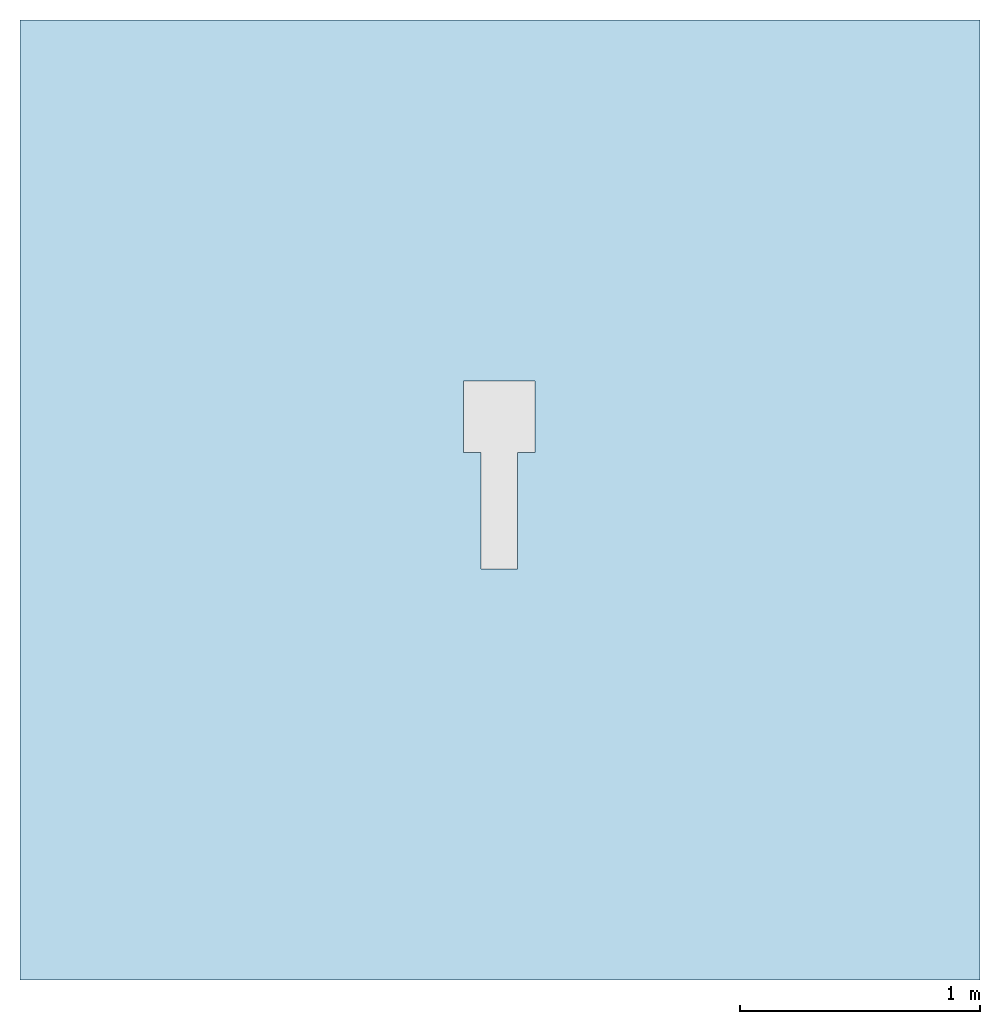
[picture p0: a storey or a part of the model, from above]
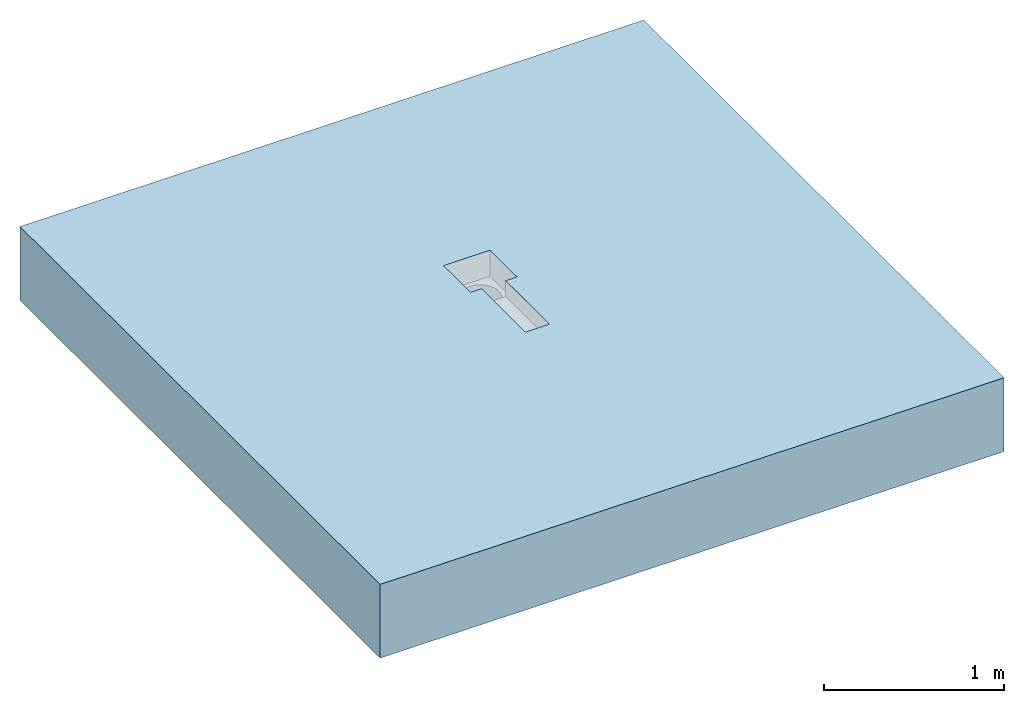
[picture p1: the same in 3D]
Properties of the parts of a building model (IFC2X3)

# File
Description: ViewDefinition [CoordinationView]
File name: 105376 - One Way Gully Top - 784 mm LG - Invert Depth 95mm.ifc
Time: 2014-03-19T12:21:46
Written by: Autodesk Revit 2013
Made in: 20120221_2030(x64)

# IfcProject, Project Number
LongName: Project Name; Phase: Project Status

# IfcSite, Default
RefLatitude: 42, 21, 30, 344238; RefLongitude: -71, -3, -35, -194702; RefElevation: 0 mm

# IfcBuilding
Pset_BuildingCommon - NumberOfStoreys: 1
Other - Client Name: Owner; Project Address: ## Street City, State Zip; Project Name: Project Name; Project Status: Project Status; Project Issue Date: Issue Date; Project Number: Project Number

# IfcBuildingStorey, Level 1
LongName: Level 1; Elevation: 0 mm
Graphics - Line Weight: 1; Symbol: M_Level Head - Circle: M_Level Head - Circle; Symbol at End 2 Default: yes; Color: 0; Line Pattern: Center; Symbol at End 1 Default: no
Constraints - Elevation Base: 0; Elevation: 0 mm
Dimensions - Computation Height: 0 mm
Identity Data - Structural: no; Name: Level 1; Building Story: yes

# IfcFlowTerminal: 105376 - One Way Gully Top - 784 mm LG - Invert Depth 95mm, ACO BD Modular 125 One and Two Way Gully Units:105376 - One Way Gully Top - 784 mm LG - Invert Depth 95mm:105376 - One Way Gully Top - 784 mm LG - Invert Depth 95mm:204969
In: Level 1
Material: Rubber, Nitrile, Stainless Steel AISI 304, Polystyrene, High Impact
Construction - Grating One Way: yes; Grating Two Way: no; Detail 125mm: no; Detail 65mm: no; Detail 95mm: yes; 49061 & 49062_Vinyl Seal: no; 402072 - Grating - Heal Safe Locked - Stainless Steel 304 - 500mm long: no; 105505 - Perforated Locked - Stainless Steel 304 - 500mm long: no; 408085_Telescopic_Horizontal Outlet Ø_110mm: no; 408067_Telescopic_Vertical Outlet Ø_160mm: no; 408223_Horizontal Outlet Gully Silt Basket: no; 105846 - Slip Resistant Intercept - Stainless Steel 304 - 500mm long: no; 408071_Telescopic_Vertical Outlet Ø_160mm: no; 105844 - Slip Resistant Quadrato Locked - Stainless Steel 304 - 500mm long: no; 408220_Outlet Foul Air Trap: yes; 408045 - Plain Ladder - Stainless Steel 304 - 268 x 268mm: no; 408041 - Slip Resistant Arla - Stainless Steel 304 - 268 x 268mm: no; 408039 - Slot Cover - Stainless Steel 304 - 268 x 268mm: no; 408038 - Ladder - Stainless Steel 304 - 268 x 268mm: no; 105537 - Intercept Locked - Stainless Steel 304 - 500mm long: no; 105848 - Slip Resistant Intercept Locked - Stainless Steel 304 - 500mm long: no; Min & Max Table for Vertical Gully Outlet: no; Min & Max Table for Horizontal Gully Outlet: no; 408065_Telescopic_Vertical Outlet Ø_110mm: no; 105842 - Slip Resistant Quadrato - Stainless Steel 304 - 500mm long: no; 10735 - Composite - White Composite - 500mm long: no; 15704 - Composite - Black Composite - 500mm long: no; 21910 - Grating - Slip Resistant Mesh - Stainless Steel 304 - 500mm long: no; 21790 - Plastic - White Plastic - 500mm long: no; 408069_Telescopic_Vertical Outlet Ø_160mm: no; 408037 - Slip Resistant Ladder - Stainless Steel 304 - 268 x 268mm: no; 408087_Telescopic_Horizontal Outlet Ø_110mm: no; 21740 - Ladder - Stainless Steel 304 - 500mm long: no; 26270_PVC Infill: yes; 408034 - Plain Mesh - Stainless Steel 304 - 268 x 268mm: no; 408089_Telescopic_Horizontal Outlet Ø_110mm: no; 408042 - Slip Resistant Multi Slot - Stainless Steel 304 - 268 x 268mm: no; 408040 - Heal Safe - Stainless Steel 304 - 268 x 268mm: no; 408035 - Slip Resistant Mesh - Stainless Steel 304 - 268 x 268mm: no; 408063_Telescopic_Vertical Outlet Ø_110mm: no; 408061_Telescopic_Vertical Outlet Ø_110mm: yes; 408036 - Quadrato - Stainless Steel 304 - 268 x 268mm: no; End Plate Invert 2: no; 96819 - Grating - Heal Safe - Stainless Steel 304 - 500mm long: no; 105519 - Slotted Locked - Stainless Steel 304 - 500mm long: no; 105521 - Slotted Locked - Stainless Steel 304 - 500mm long: no; 105528 - Quadrato Locked - Stainless Steel 304 - 500mm long: no; End Plate Invert 1: no; 408222_Verical Outlet Gully Silt Basket: yes; 105539 - Intercept - Stainless Steel 304 - 500mm long: no; 21710 - Grating - Slip Resistant Mesh - Stainless Steel 304 - 500mm long: no; 21920 - Grating - Plain Mesh - Stainless Steel 304 - 500mm long: no; 105530 - Quadrato - Stainless Steel 304 - 500mm long: no; 21720 - Grating - Plain Mesh - Stainless Steel 304 - 500mm long: no
Other - Rigid PVC Extrusion (49061): 0 mm; Neoprene Gasket: 1; 408089: 400 mm; 408063: 400 mm; PVC Infill Two Way: no; 408071: 400 mm; 408061: 0 mm; 408065: 400 mm; Silt Basket: yes; 408069: 400 mm; 408085: 400 mm; PVC Infill (26270): 1983 mm; 408067: 400 mm; 408087: 400 mm; Flexible PVC Seal (49062): 0 mm; One Way Detail 125mm: no; Two Way Detail 65mm: no; One Way Detail 65mm: no; One Way Channel: yes; Two Way Detail 125mm: no; Two Way Detail 95mm: no; One Way Detail 95mm: yes; Two Way Channel: no
Identity Data - Mark: 2; Watermarked By: www.acobd.com; Telephone: +44 (0)1462 816666; Manufacturer: ACO Building Drainage; E-mail Sales: abdcommercial@aco.co.uk; Website: www.acobd.com; Address: ACO Business Centre, Caxton Road, Bedford, MK41 0LF; E-mail Technical: abdtechnical@aco.co.uk; Fax: +44 (0)1462 851490; Watermark2: This file is water marked and users are prohibited to reproduce, adapt, distribute this information.; Watermark1: This file is the property of ACO Technologies PLC.; Watermarked With: BIM Manager Premium Suite.
Mechanical - System Classification: Sanitary
Dimensions - Silt Basket Height: 50 mm; Vertical Gully Void Height Start: -18.5 mm; Horizontal Gully Outlet Radius: 0 mm; Horizontal Gully Void Height Start: -1 mm; Vertical Gully Void Height End: -290.5 mm; Gully Floor Void Radius: 120 mm; Vertical Gully Outlet Radius: 55 mm; Horizontal Gully Void Height End: 1 mm; Gully Top Floor Void End: 176.25 mm; Depth: 74 mm; Channel Floor Void Height: 107.8 mm; Channel Floor Void End: 486 mm; Grating Height: 21 mm; Gully Height from Floor: 139 mm; PVC 1 or 2 way: 147.5 mm; Channel to Gully top cutter End: 121 mm; Total Height: 107.8 mm; Two Way PVC In Filll Start: -1.5 mm
Constraints - Level: Level: Level 1
Phasing - Phase Created: New Construction
General - Installation guidelines: X:\Electronic Literature\ABD Electronic Literature\Standard Stainless Steel and Galvanised Steel Channels\ACO Modular 125\ACO Modular 125.pdf; Product Code: 105376; Product Range: ACO Modular 125; Weight (Kg): 5.2; Product Description: ACO Modular 125 One Way Gully Top; NBS Specification: NBS Section Q10 Kerbs/edgings/channels/paving accessories, Clause 180 Drainage Channel Systems; Channel Material: Stainless Steel Grade 304; Channel Recyclable: Fully recyclable; Product Type: Stainless Steel Channel Drainage System; Price: POA - contact ACO; Seal Recyclable: Fully recyclable; Product Standard: BS EN 1433:2002, CE marked; Channel Colour: Mid Grey; Channel Recycled Material Content: 60-70%; Seal Colour: Black; Dimensions (LxWxH): 784 x 153 x 95; Load Class: A15 - C250; Seal Recycled Material Content: 0%; Maintenance guidelines: X:\Electronic Literature\ABD Electronic Literature\Standard Stainless Steel and Galvanised Steel Channels\ACO Modular 125\ACO Modular 125.pdf; Seal Material: Neoprene
Model Properties - Grating Product Code 402072: Load Class B125 - Heal Safe Locked - Stainless Steel 304 - 500mm long - 2.0kg; Grating Product Code 408035: Load Class L15 - Slip Resistant Mesh - Stainless Steel 304 - 268 x 268 mm - 2.1kg; Product Code 408223: Horizontal Outlet Gully - Silt Basket - 0.7 litre capacity - Stainless Steel 304 - 0.6kg; Grating Product Code 408037: Load Class M125 - Slip Resistant Ladder - Stainless Steel 304 - 268 x 268 mm - 4.3kg; Grating Product Code 105519: Load Class A15 - Slotted Locked - Stainless Steel 304 - 500mm long - 1.0kg; Product Code 408225: Friction Ring Installation Set - Nitrile - 0.09kg; Grating Product Code 408038: Load Class M125 - Plain Ladder - Stainless Steel 304 - 268 x 268 mm - 4.3kg; Grating Product Code 408039: Load Class M125 - Slot Cover - Stainless Steel 304 - 268 x 268 mm - 6.0kg; Gully Product Code 408063: Telescopic - 110mm Ø Vertical Outlet - Stainless Steel 304 - Adhesive Bonding Flange - Flow Rate 5.0 to 6.3 l/s - 4.4kg; Gully Product Code 408067: Telescopic - 160mm Ø Vertical Outlet - Stainless Steel 304 - Location Flange - Flow Rate 5.0 to 6.3 l/s - 3.2kg; Grating Product Code 96819: Load Class B125 - Heal Safe - Stainless Steel 304 - 500mm long - 2.0kg; Grating Product Code 15704: Load Class C250 - Composite - Black Composite - 500mm long - 1.2kg; Gully Product Code 408069: Telescopic - 160mm Ø Vertical Outlet - Stainless Steel 304 - Adhesive Bonding Flange - Flow Rate 5.0 to 6.3 l/s - 4.4kg; Gully Product Code 408061: Telescopic - 110mm Ø Vertical Outlet - Stainless Steel 304 - Location Flange - Flow Rate 5.0 to 6.3 l/s - 3.2kg; Grating Product Code 408041: Load Class L15 - Slip Resistant Arla - Stainless Steel 304 - 268 x 268 mm - 1.8kg; Grating Product Code 105848: Load Class A15 - Slip Resistant Intercept Locked - Stainless Steel 304 - 500mm long - 1.8kg; Grating Product Code 21920: Load Class C250 - Plain Mesh - Stainless Steel 304 - 500mm long - 2.2kg; Grating Product Code 21740: Load Class C250 - Ladder - Stainless Steel 304 - 500mm long - 2.0kg; Grating Product Code 408034: Load Class L15 - Plain Mesh - Stainless Steel 304 - 268 x 268 mm - 2.1kg; Grating Product Code 408040: Load Class L15 - Heal Safe - Stainless Steel 304 - 268 x 268 mm - 2.4kg; Gully Product Code 408065: Telescopic - 110mm Ø Vertical Outlet - Stainless Steel 304 - Mechanical Clamping Flange - Flow Rate 5.0 to 6.3 l/s - 5.5kg; Grating Product Code 408042: Load Class L15 - Slip Resistant Multi Slot - Stainless Steel 304 - 268 x 268 mm - 2.0kg; Grating Product Code 408045: Load Class C250 - Plain Ladder - Stainless Steel 304 - 268 x 268 mm - 6.2kg; Grating Product Code 105846: Load Class A15 - Slip Resistant Intercept - Stainless Steel 304 - 500mm long - 1.8kg; Product Code 408222: Vertical Outlet Gully - Silt Basket - 1.4 litre capacity - Stainless Steel 304 - 0.7kg; Grating Product Code 105844: Load Class A15 - Slip Resistant Quadrato Locked - Stainless Steel 304 - 500mm long - 1.6kg; Gully Product Code 408087: Telescopic - 110mm Ø Horizontal Outlet - Stainless Steel 304 - Adhesive Bonding Flange - Flow Rate 4.4 to 5.5 l/s - 4.2kg; Grating Product Code 21790: Load Class A15 - Plastic - White Plastic - 500mm long - 0.6kg; Grating Product Code 21910: Load Class C250 - Slip Resistant Mesh - Stainless Steel 304 - 500mm long - 2.2kg; Grating Product Code 105530: Load Class A15 - Quadrato - Stainless Steel 304 - 500mm long - 1.6kg; Grating Product Code 105539: Load Class A15 - Intercept - Stainless Steel 304 - 500mm long - 1.8kg; Gully Product Code 408089: Telescopic - 110mm Ø Horizontal Outlet - Stainless Steel 304 - Mechanical Clamping Flange - Flow Rate 4.4 to 5.5 l/s - 4.4kg; Grating Product Code 105528: Load Class A15 - Quadrato Locked - Stainless Steel 304 - 500mm long - 1.6kg; End Plate Product Code 105103: End Plate Stainless Steel 304 for Invert Depth - 95mm - 0.24Kg; Product Code 408221: Foul Air Trap Support Ring - Nitrile - 0.2kg; Grating Product Code 105521: Load Class C250 - Slotted Locked - Stainless Steel 304 - 500mm long - 2.3kg; Grating Product Code 10735: Load Class C250 - Composite - White Composite - 500mm long - 1.2kg; End Plate Product Code 105101: N/A; Grating Product Code 105537: Load Class A15 - Intercept Locked - Stainless Steel 304 - 500mm long - 1.8kg; End Plate Product Code 105105: N/A; Grating Product Code 21720: Load Class A15 - Plain Mesh - Stainless Steel 304 - 500mm long - 1.6kg; Product Code 408220: Outlet Foul Air Trap - Stainless Steel 304 - 1.2kg; Grating Product Code 408036: Load Class L15 - Quadrato - Stainless Steel 304 - 268 x 268 mm - 1.8kg; Grating Product Code 21710: Load Class A15 - Slip Resistant Mesh - Stainless Steel 304 - 500mm long - 1.6kg; Gully Product Code 408071: Telescopic - 160mm Ø Vertical Outlet - Stainless Steel 304 - Mechanical Clamping Flange - Flow Rate 5.0 to 6.3 l/s - 5.5kg; Grating Product Code 105505: Load Class C250 - Perforated Locked - Stainless Steel 304 - 500mm long - 1.8kg; Grating Product Code 105842: Load Class A15 - Slip Resistant Quadrato - Stainless Steel 304 - 500mm long - 1.6kg; Gully Product Code 408085: Telescopic - 110mm Ø Horizontal Outlet - Stainless Steel 304 - Location Flange - Flow Rate 4.4 to 5.5 l/s - 2.2kg

# IfcOpeningElement: Recess
In: Level 1
Constraints - Related to Mass: no; Height Offset From Level: 0 mm; Room Bounding: yes; Level: Level: Level 1
Structural - Structural: no; Enable Analytical Model: no
Phasing - Phase Created: New Construction
Dimensions - Volume: 7965835978 mm3; Thickness: 500 mm; Perimeter: 16000 mm; Area: 16000000 mm2
Analytical Properties - Thermal mass: 755550; Absorptance: 0.1; Roughness: 1; Thermal Resistance (R): 0.478011; Heat Transfer Coefficient (U): 2.092
Materials and Finishes - Structural Material: Concrete, Broom Finish
Construction - Function: 0; Default Thickness: 500 mm
Graphics - Coarse Scale Fill Color: 0

# IfcSlab: Floor:Generic Floor - 500mm, Floor:Generic Floor - 500mm:193825
In: Level 1
PredefinedType: FLOOR; Material: Concrete, Broom Finish 500 mm
Constraints - Related to Mass: no; Height Offset From Level: 0 mm; Room Bounding: yes; Level: Level: Level 1
Structural - Structural: no; Enable Analytical Model: no
Phasing - Phase Created: New Construction
Dimensions - Volume: 7965835978 mm3; Thickness: 500 mm; Perimeter: 16000 mm; Area: 16000000 mm2
Pset_SlabCommon - Reference: Generic Floor - 500mm; IsExternal: no; LoadBearing: yes
Analytical Properties - Thermal mass: 755550; Absorptance: 0.1; Roughness: 1; Thermal Resistance (R): 0.478011; Heat Transfer Coefficient (U): 2.092
Materials and Finishes - Structural Material: Concrete, Broom Finish
Construction - Function: 0; Default Thickness: 500 mm
Graphics - Coarse Scale Fill Color: 0
